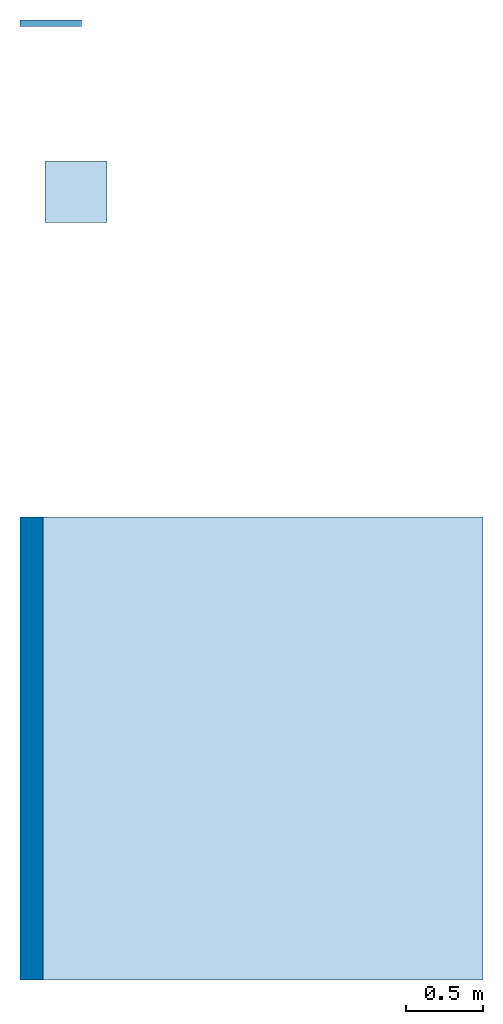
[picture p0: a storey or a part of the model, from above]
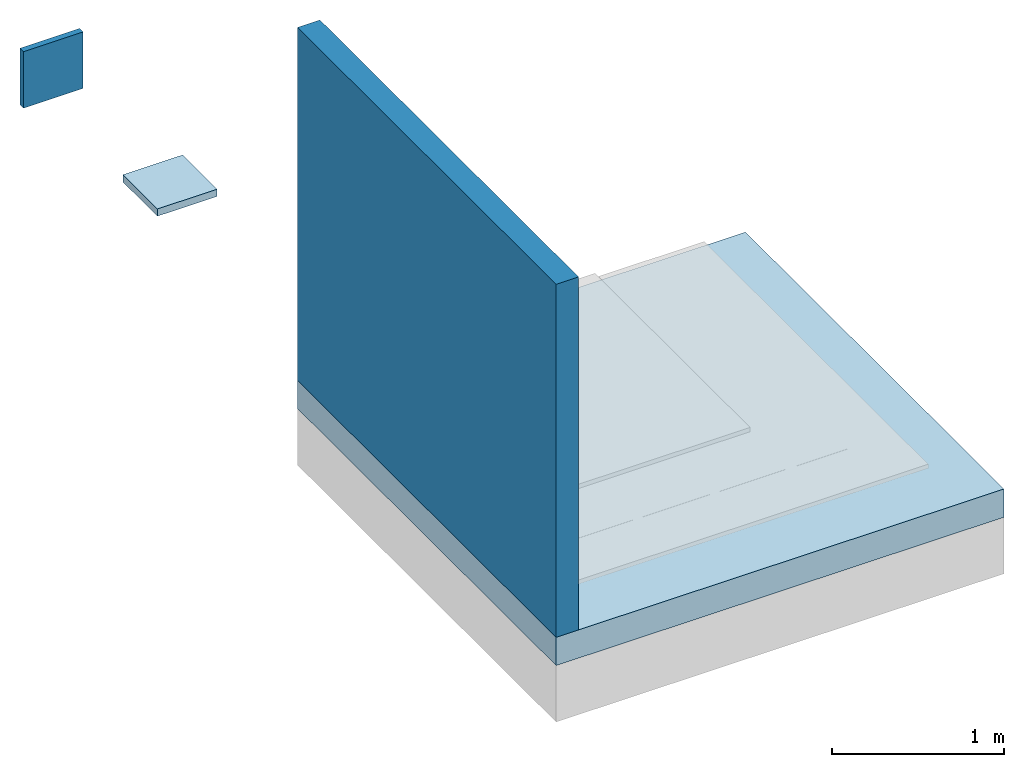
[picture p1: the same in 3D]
Properties of the parts of a building model (IFC2X3)

# File
Description: ViewDefinition [CoordinationView_V2.0], RevitIdentifiers [VersionGUID: ed9ac4b5-e8cb-44a9-bade-2b4062fd3fcd, NumberOfSaves: 16], CoordinateReference [CoordinateBase: Coordenadas compartilhadas]
File name: 0001
Time: 2025-04-16T11:34:34
Written by: ODA IFC SDK 22.8
Made in: 22.1.50.17 - Exporter 22.6.2.0 - IU alternativa 22.6.2.0

# IfcProject, 0001
LongName: Circulação de Veículos em contato com o solo - VIAPLUS 2000 Fibras; Phase: Status do projeto

# IfcSite, Default
RefLatitude: 42, 21, 31, 181944; RefLongitude: -71, -3, -24, -263304; RefElevation: 0 m

# IfcBuilding
Pset_BuildingCommon - NumberOfStoreys: 1; IsLandmarked: no

# IfcBuildingStorey: Nível:Cabeça de 8 mm, ARQ Térreo
LongName: ARQ Térreo; Elevation: -0.0025238 m

# IfcBuildingElementProxy: IMPER:IMPER:433934, IMPER:IMPER:433934:IMPER:433934 : IMPER:IMPER:433934:291594
In: ARQ Térreo
Type - Material: #argamassa, #Viaplus 1000, #Proteção Mecânica, #solo
Type - Pset_BuildingElementProxyCommon - Reference: IMPER
Type - Pset_QuantityTakeOff - Reference: IMPER
Type - Pset_ProvisionForVoid - Width: 0.952886 m; Height: 0.00103887 m; Depth: 2.6 m
Pset_BuildingElementProxyCommon - sets with these values: 2

# IfcSlab: Piso:IMPH_VP2000, Piso:IMPH_VP2000:293954
In: ARQ Térreo
Type - PredefinedType: FLOOR; Material: #Proteção Mecânica 0.03 m, #Viaplus 1000 0.001 m, #argamassa 0.02 m
Type - Pset_SlabCommon - IsExternal: no
Pset_QuantityTakeOff - Reference: IMPH_VP2000; sets with these values: 2
Pset_SlabCommon - LoadBearing: no; PitchAngle: 0 deg; Reference: IMPH_VP2000

# IfcSlab: Piso:Piso:LAJE CONCRETO, Piso:Piso:LAJE CONCRETO:293935
In: ARQ Térreo
Type - PredefinedType: FLOOR; Material: #concreto 0.2 m
Type - Pset_SlabCommon - IsExternal: no
Pset_QuantityTakeOff - Reference: Piso:LAJE CONCRETO; sets with these values: 2
Pset_SlabCommon - Reference: Piso:LAJE CONCRETO; LoadBearing: no; PitchAngle: 0 deg

# IfcWallStandardCase: Parede básica:IMPV_VP2000, Parede básica:IMPV_VP1000:459587
In: ARQ Térreo
Type - PredefinedType: STANDARD; Material: #Proteção Mecânica 0.03 m, #Viaplus 1000 0.001 m, #argamassa 0.01 m
Type - Pset_WallCommon - IsExternal: yes; ThermalTransmittance: 16.4516 kg/K/s3
Pset_QuantityTakeOff - Reference: IMPV_VP1000; sets with these values: 2
Pset_WallCommon - LoadBearing: no; ExtendToStructure: no; Reference: IMPV_VP1000

# IfcWallStandardCase: Parede básica:Parede básica:Parede Concreto, Parede básica:Parede Concreto:395312
In: ARQ Térreo
Type - PredefinedType: STANDARD; Material: #concreto 0.15 m
Type - Pset_WallCommon - IsExternal: yes; ThermalTransmittance: 6.97333 kg/K/s3
Pset_QuantityTakeOff - Reference: Parede Concreto; sets with these values: 2
Pset_WallCommon - LoadBearing: no; Reference: Parede Concreto; ExtendToStructure: no
